One B-rep face of a CAD part: STEP entity #26056.
In plain terms, the planar face has unit normal (0, 0, -1).
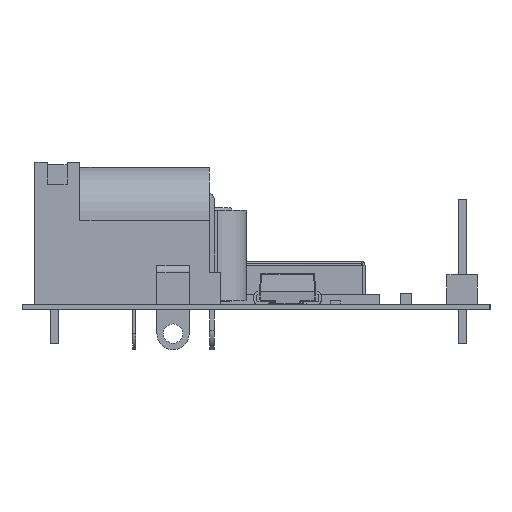
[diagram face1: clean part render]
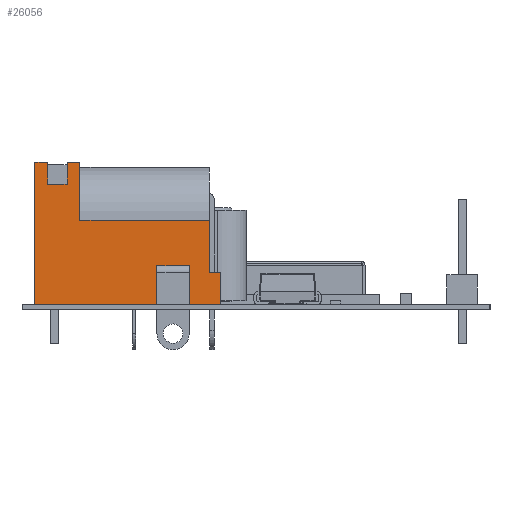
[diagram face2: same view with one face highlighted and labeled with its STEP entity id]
Its self-contained STEP definition (entity closure, numbers rounded to 3 decimals):
#25893 = VERTEX_POINT('',#25894);
#25894 = CARTESIAN_POINT('',(-14.4,-6.5,-4.5));
#25900 = EDGE_CURVE('',#25893,#25901,#25903,.T.);
#25901 = VERTEX_POINT('',#25902);
#25902 = CARTESIAN_POINT('',(-11.95,-6.5,-4.5));
#25903 = LINE('',#25904,#25905);
#25904 = CARTESIAN_POINT('',(-14.4,-6.5,-4.5));
#25905 = VECTOR('',#25906,1.);
#25906 = DIRECTION('',(1.,0.,0.));
#25909 = VERTEX_POINT('',#25910);
#25910 = CARTESIAN_POINT('',(-9.45,-6.5,-4.5));
#25916 = EDGE_CURVE('',#25909,#25917,#25919,.T.);
#25917 = VERTEX_POINT('',#25918);
#25918 = CARTESIAN_POINT('',(0.,-6.5,-4.5));
#25919 = LINE('',#25920,#25921);
#25920 = CARTESIAN_POINT('',(-14.4,-6.5,-4.5));
#25921 = VECTOR('',#25922,1.);
#25922 = DIRECTION('',(1.,0.,0.));
#26007 = VERTEX_POINT('',#26008);
#26008 = CARTESIAN_POINT('',(-13.5,-4.,-4.5));
#26014 = EDGE_CURVE('',#26007,#26015,#26017,.T.);
#26015 = VERTEX_POINT('',#26016);
#26016 = CARTESIAN_POINT('',(-14.4,-4.,-4.5));
#26017 = LINE('',#26018,#26019);
#26018 = CARTESIAN_POINT('',(-14.4,-4.,-4.5));
#26019 = VECTOR('',#26020,1.);
#26020 = DIRECTION('',(-1.,0.,0.));
#26056 = ADVANCED_FACE('',(#26057),#26160,.T.);
#26057 = FACE_BOUND('',#26058,.T.);
#26058 = EDGE_LOOP('',(#26059,#26060,#26068,#26076,#26082,#26083,#26089,
    #26090,#26098,#26106,#26114,#26122,#26130,#26138,#26146,#26154));
#26059 = ORIENTED_EDGE('',*,*,#25916,.F.);
#26060 = ORIENTED_EDGE('',*,*,#26061,.T.);
#26061 = EDGE_CURVE('',#25909,#26062,#26064,.T.);
#26062 = VERTEX_POINT('',#26063);
#26063 = CARTESIAN_POINT('',(-9.45,-3.5,-4.5));
#26064 = LINE('',#26065,#26066);
#26065 = CARTESIAN_POINT('',(-9.45,-10.,-4.5));
#26066 = VECTOR('',#26067,1.);
#26067 = DIRECTION('',(0.,1.,0.));
#26068 = ORIENTED_EDGE('',*,*,#26069,.T.);
#26069 = EDGE_CURVE('',#26062,#26070,#26072,.T.);
#26070 = VERTEX_POINT('',#26071);
#26071 = CARTESIAN_POINT('',(-11.95,-3.5,-4.5));
#26072 = LINE('',#26073,#26074);
#26073 = CARTESIAN_POINT('',(-11.95,-3.5,-4.5));
#26074 = VECTOR('',#26075,1.);
#26075 = DIRECTION('',(-1.,0.,0.));
#26076 = ORIENTED_EDGE('',*,*,#26077,.F.);
#26077 = EDGE_CURVE('',#25901,#26070,#26078,.T.);
#26078 = LINE('',#26079,#26080);
#26079 = CARTESIAN_POINT('',(-11.95,-10.,-4.5));
#26080 = VECTOR('',#26081,1.);
#26081 = DIRECTION('',(0.,1.,0.));
#26082 = ORIENTED_EDGE('',*,*,#25900,.F.);
#26083 = ORIENTED_EDGE('',*,*,#26084,.T.);
#26084 = EDGE_CURVE('',#25893,#26015,#26085,.T.);
#26085 = LINE('',#26086,#26087);
#26086 = CARTESIAN_POINT('',(-14.4,4.5,-4.5));
#26087 = VECTOR('',#26088,1.);
#26088 = DIRECTION('',(0.,1.,0.));
#26089 = ORIENTED_EDGE('',*,*,#26014,.F.);
#26090 = ORIENTED_EDGE('',*,*,#26091,.F.);
#26091 = EDGE_CURVE('',#26092,#26007,#26094,.T.);
#26092 = VERTEX_POINT('',#26093);
#26093 = CARTESIAN_POINT('',(-13.5,0.,-4.5));
#26094 = LINE('',#26095,#26096);
#26095 = CARTESIAN_POINT('',(-13.5,-4.,-4.5));
#26096 = VECTOR('',#26097,1.);
#26097 = DIRECTION('',(0.,-1.,0.));
#26098 = ORIENTED_EDGE('',*,*,#26099,.T.);
#26099 = EDGE_CURVE('',#26092,#26100,#26102,.T.);
#26100 = VERTEX_POINT('',#26101);
#26101 = CARTESIAN_POINT('',(-3.5,0.,-4.5));
#26102 = LINE('',#26103,#26104);
#26103 = CARTESIAN_POINT('',(-14.4,0.,-4.5));
#26104 = VECTOR('',#26105,1.);
#26105 = DIRECTION('',(1.,0.,0.));
#26106 = ORIENTED_EDGE('',*,*,#26107,.T.);
#26107 = EDGE_CURVE('',#26100,#26108,#26110,.T.);
#26108 = VERTEX_POINT('',#26109);
#26109 = CARTESIAN_POINT('',(-3.5,4.5,-4.5));
#26110 = LINE('',#26111,#26112);
#26111 = CARTESIAN_POINT('',(-3.5,0.,-4.5));
#26112 = VECTOR('',#26113,1.);
#26113 = DIRECTION('',(0.,1.,0.));
#26114 = ORIENTED_EDGE('',*,*,#26115,.T.);
#26115 = EDGE_CURVE('',#26108,#26116,#26118,.T.);
#26116 = VERTEX_POINT('',#26117);
#26117 = CARTESIAN_POINT('',(-2.5,4.5,-4.5));
#26118 = LINE('',#26119,#26120);
#26119 = CARTESIAN_POINT('',(-14.4,4.5,-4.5));
#26120 = VECTOR('',#26121,1.);
#26121 = DIRECTION('',(1.,0.,0.));
#26122 = ORIENTED_EDGE('',*,*,#26123,.F.);
#26123 = EDGE_CURVE('',#26124,#26116,#26126,.T.);
#26124 = VERTEX_POINT('',#26125);
#26125 = CARTESIAN_POINT('',(-2.5,2.8,-4.5));
#26126 = LINE('',#26127,#26128);
#26127 = CARTESIAN_POINT('',(-2.5,2.8,-4.5));
#26128 = VECTOR('',#26129,1.);
#26129 = DIRECTION('',(0.,1.,0.));
#26130 = ORIENTED_EDGE('',*,*,#26131,.F.);
#26131 = EDGE_CURVE('',#26132,#26124,#26134,.T.);
#26132 = VERTEX_POINT('',#26133);
#26133 = CARTESIAN_POINT('',(-1.,2.8,-4.5));
#26134 = LINE('',#26135,#26136);
#26135 = CARTESIAN_POINT('',(-1.,2.8,-4.5));
#26136 = VECTOR('',#26137,1.);
#26137 = DIRECTION('',(-1.,0.,0.));
#26138 = ORIENTED_EDGE('',*,*,#26139,.T.);
#26139 = EDGE_CURVE('',#26132,#26140,#26142,.T.);
#26140 = VERTEX_POINT('',#26141);
#26141 = CARTESIAN_POINT('',(-1.,4.5,-4.5));
#26142 = LINE('',#26143,#26144);
#26143 = CARTESIAN_POINT('',(-1.,2.8,-4.5));
#26144 = VECTOR('',#26145,1.);
#26145 = DIRECTION('',(0.,1.,0.));
#26146 = ORIENTED_EDGE('',*,*,#26147,.T.);
#26147 = EDGE_CURVE('',#26140,#26148,#26150,.T.);
#26148 = VERTEX_POINT('',#26149);
#26149 = CARTESIAN_POINT('',(0.,4.5,-4.5));
#26150 = LINE('',#26151,#26152);
#26151 = CARTESIAN_POINT('',(-14.4,4.5,-4.5));
#26152 = VECTOR('',#26153,1.);
#26153 = DIRECTION('',(1.,0.,0.));
#26154 = ORIENTED_EDGE('',*,*,#26155,.F.);
#26155 = EDGE_CURVE('',#25917,#26148,#26156,.T.);
#26156 = LINE('',#26157,#26158);
#26157 = CARTESIAN_POINT('',(0.,4.5,-4.5));
#26158 = VECTOR('',#26159,1.);
#26159 = DIRECTION('',(0.,1.,0.));
#26160 = PLANE('',#26161);
#26161 = AXIS2_PLACEMENT_3D('',#26162,#26163,#26164);
#26162 = CARTESIAN_POINT('',(-14.4,4.5,-4.5));
#26163 = DIRECTION('',(0.,0.,-1.));
#26164 = DIRECTION('',(-1.,0.,0.));
